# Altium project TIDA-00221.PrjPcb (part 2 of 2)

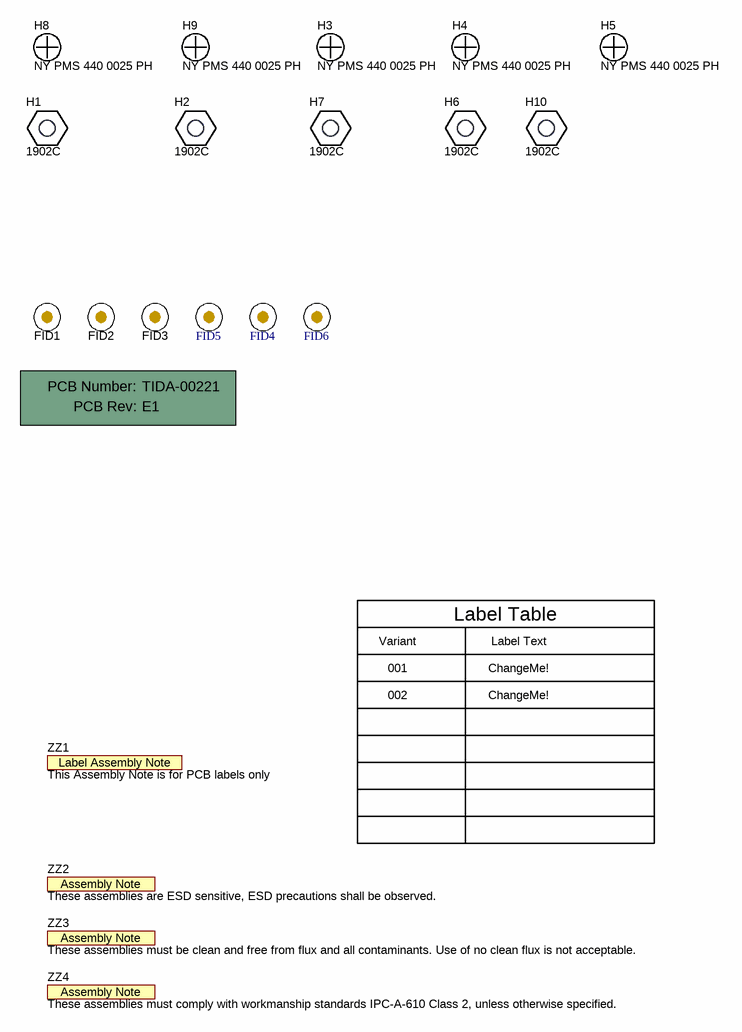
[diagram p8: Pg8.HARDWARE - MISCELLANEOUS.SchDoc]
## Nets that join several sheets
12V: Pg4.Analog Front End Opamp (Voltage) + LDO + ZCD (6 pins), Pg5.JTAG Interface + LEDs + Decoupling Capacitors (R1.2 R2.2)
AGND: Pg3.Analog Front End (Current) (42 pins), Pg4.Analog Front End Opamp (Voltage) + LDO + ZCD (12 pins), Pg5.JTAG Interface + LEDs + Decoupling Capacitors (8 pins), Pg6.MSP430F6779 + Crystal (U3.112 U3.120)
AVCC: Pg4.Analog Front End Opamp (Voltage) + LDO + ZCD (C10.2 R29.1 U2.4), Pg5.JTAG Interface + LEDs + Decoupling Capacitors (C54.1 C55.1 R72.2), Pg6.MSP430F6779 + Crystal (U3.121)
DGND: Pg4.Analog Front End Opamp (Voltage) + LDO + ZCD (11 pins), Pg5.JTAG Interface + LEDs + Decoupling Capacitors (22 pins), Pg6.MSP430F6779 + Crystal (8 pins), Pg7.Interfaces (J1.4)
DVCC: Pg4.Analog Front End Opamp (Voltage) + LDO + ZCD (5 pins), Pg5.JTAG Interface + LEDs + Decoupling Capacitors (9 pins), Pg6.MSP430F6779 + Crystal (5 pins), Pg7.Interfaces (J1.5)
NEUTRAL: Pg3.Analog Front End (Current) (R41.1), Pg4.Analog Front End Opamp (Voltage) + LDO + ZCD (FB1.1 J7.2)
VASYS1: Pg5.JTAG Interface + LEDs + Decoupling Capacitors (C50.1 C51.1 C56.1 C57.1), Pg6.MSP430F6779 + Crystal (U3.111 U3.122)
Active_LED: Pg5.JTAG Interface + LEDs + Decoupling Capacitors (R4.1), Pg6.MSP430F6779 + Crystal (U3.26)
AUXVCC1: Pg5.JTAG Interface + LEDs + Decoupling Capacitors (C41.1 C43.1 TP15.1), Pg6.MSP430F6779 + Crystal (U3.124)
AUXVCC2: Pg5.JTAG Interface + LEDs + Decoupling Capacitors (C40.1 C42.1), Pg6.MSP430F6779 + Crystal (U3.123)
AUXVCC3: Pg5.JTAG Interface + LEDs + Decoupling Capacitors (C47.1 C48.1 TP14.1), Pg6.MSP430F6779 + Crystal (R70.2 U3.3)
Calib_LED: Pg5.JTAG Interface + LEDs + Decoupling Capacitors (R3.1), Pg6.MSP430F6779 + Crystal (U3.27)
I1+: Pg3.Analog Front End (Current) (C18.1 C31.1 R42.1), Pg6.MSP430F6779 + Crystal (U3.103)
I1-: Pg3.Analog Front End (Current) (C18.2 C32.2 R43.1), Pg6.MSP430F6779 + Crystal (U3.104)
I2+: Pg3.Analog Front End (Current) (C19.1 C33.1 R44.1), Pg6.MSP430F6779 + Crystal (U3.105)
I2-: Pg3.Analog Front End (Current) (C19.2 C34.2 R45.1), Pg6.MSP430F6779 + Crystal (U3.106)
I3+: Pg3.Analog Front End (Current) (C20.1 C35.1 R46.1), Pg6.MSP430F6779 + Crystal (U3.107)
I3-: Pg3.Analog Front End (Current) (C20.2 C36.2 R47.1), Pg6.MSP430F6779 + Crystal (U3.108)
I4+: Pg3.Analog Front End (Current) (C21.1 C37.1 R33.1), Pg6.MSP430F6779 + Crystal (U3.109)
I4-: Pg3.Analog Front End (Current) (C21.2 C38.2 R34.1), Pg6.MSP430F6779 + Crystal (U3.110)
I5+: Pg3.Analog Front End (Current) (C22.1 C25.1 R35.1), Pg6.MSP430F6779 + Crystal (U3.114)
I5-: Pg3.Analog Front End (Current) (C22.2 C26.2 R36.1), Pg6.MSP430F6779 + Crystal (U3.115)
I6+: Pg3.Analog Front End (Current) (C23.1 C27.1 R37.1), Pg6.MSP430F6779 + Crystal (U3.116)
I6-: Pg3.Analog Front End (Current) (C23.2 C28.2 R38.1), Pg6.MSP430F6779 + Crystal (U3.117)
I7+: Pg3.Analog Front End (Current) (C24.1 C29.1 R39.1), Pg6.MSP430F6779 + Crystal (U3.118)
I7-: Pg3.Analog Front End (Current) (C24.2 C30.2 R40.1), Pg6.MSP430F6779 + Crystal (U3.119)
P1.0: Pg6.MSP430F6779 + Crystal (U3.11), Pg7.Interfaces (J4.3)
P1.1: Pg6.MSP430F6779 + Crystal (U3.10), Pg7.Interfaces (J4.2)
P1.2: Pg6.MSP430F6779 + Crystal (U3.9), Pg7.Interfaces (J4.1)
P2.4: Pg6.MSP430F6779 + Crystal (U3.12), Pg7.Interfaces (J4.4)
P2.7: Pg6.MSP430F6779 + Crystal (U3.15), Pg7.Interfaces (J1.3)
P3.2: Pg6.MSP430F6779 + Crystal (U3.18), Pg7.Interfaces (J4.7)
P4.3: Pg6.MSP430F6779 + Crystal (U3.41), Pg7.Interfaces (J3.11)
P4.6: Pg6.MSP430F6779 + Crystal (U3.44), Pg7.Interfaces (J3.14)
P4.7: Pg6.MSP430F6779 + Crystal (U3.45), Pg7.Interfaces (J3.15)
P5.5: Pg6.MSP430F6779 + Crystal (R64.1 R65.1 U3.32), Pg7.Interfaces (J3.2)
P5.6: Pg6.MSP430F6779 + Crystal (U3.33), Pg7.Interfaces (J3.3)
P5.7: Pg6.MSP430F6779 + Crystal (U3.34), Pg7.Interfaces (J3.4)
P6.0: Pg6.MSP430F6779 + Crystal (U3.35), Pg7.Interfaces (J3.5)
P6.1: Pg6.MSP430F6779 + Crystal (U3.46), Pg7.Interfaces (J2.1)
P6.2: Pg6.MSP430F6779 + Crystal (U3.47), Pg7.Interfaces (J2.2)
P6.3: Pg6.MSP430F6779 + Crystal (U3.48), Pg7.Interfaces (J2.3)
P6.4: Pg6.MSP430F6779 + Crystal (U3.49), Pg7.Interfaces (J2.4)
P6.5: Pg6.MSP430F6779 + Crystal (U3.50), Pg7.Interfaces (J2.5)
P6.6: Pg6.MSP430F6779 + Crystal (U3.51), Pg7.Interfaces (J2.6)
P6.7: Pg6.MSP430F6779 + Crystal (U3.52), Pg7.Interfaces (J2.7)
P7.0: Pg6.MSP430F6779 + Crystal (U3.53), Pg7.Interfaces (J2.8)
P7.1: Pg6.MSP430F6779 + Crystal (U3.54), Pg7.Interfaces (J2.9)
P7.2: Pg6.MSP430F6779 + Crystal (U3.55), Pg7.Interfaces (J2.10)
P7.3: Pg6.MSP430F6779 + Crystal (U3.56), Pg7.Interfaces (J2.11)
P7.4: Pg6.MSP430F6779 + Crystal (U3.57), Pg7.Interfaces (J2.12)
P7.5: Pg6.MSP430F6779 + Crystal (U3.58), Pg7.Interfaces (J2.13)
P7.6: Pg6.MSP430F6779 + Crystal (U3.59), Pg7.Interfaces (J2.14)
P7.7: Pg6.MSP430F6779 + Crystal (U3.60), Pg7.Interfaces (J2.15)
P8.0: Pg6.MSP430F6779 + Crystal (U3.61), Pg7.Interfaces (J2.16)
P8.1: Pg6.MSP430F6779 + Crystal (U3.62), Pg7.Interfaces (J2.17)
P8.2: Pg6.MSP430F6779 + Crystal (U3.63), Pg7.Interfaces (J2.18)
P8.3: Pg6.MSP430F6779 + Crystal (U3.64), Pg7.Interfaces (J2.19)
P8.4: Pg6.MSP430F6779 + Crystal (U3.65), Pg7.Interfaces (J2.20)
P8.5: Pg6.MSP430F6779 + Crystal (U3.66), Pg7.Interfaces (J2.21)
P8.6: Pg6.MSP430F6779 + Crystal (U3.67), Pg7.Interfaces (J2.22)
P8.7: Pg6.MSP430F6779 + Crystal (U3.68), Pg7.Interfaces (J2.23)
PM_UCA0RXD: Pg6.MSP430F6779 + Crystal (U3.16), Pg7.Interfaces (J1.2)
PM_UCA0TXD: Pg6.MSP430F6779 + Crystal (U3.17), Pg7.Interfaces (J1.1)
PM_UCA1CLK: Pg6.MSP430F6779 + Crystal (U3.19), Pg7.Interfaces (J4.8)
PM_UCA1SIMO: Pg6.MSP430F6779 + Crystal (U3.21), Pg7.Interfaces (J4.10)
PM_UCA1SOMI: Pg6.MSP430F6779 + Crystal (U3.20), Pg7.Interfaces (J4.9)
PM_UCA2CLK: Pg6.MSP430F6779 + Crystal (U3.38), Pg7.Interfaces (J3.8)
PM_UCA2SIMO: Pg6.MSP430F6779 + Crystal (U3.37), Pg7.Interfaces (J3.7)
PM_UCA2SOMI: Pg6.MSP430F6779 + Crystal (U3.36), Pg7.Interfaces (J3.6)
PM_UCA3RXD: Pg6.MSP430F6779 + Crystal (U3.39), Pg7.Interfaces (J3.9)
PM_UCA3TXD: Pg6.MSP430F6779 + Crystal (U3.40), Pg7.Interfaces (J3.10)
PM_UCB0SCL: Pg6.MSP430F6779 + Crystal (R69.1 U3.13), Pg7.Interfaces (J4.5)
PM_UCB0SDA: Pg6.MSP430F6779 + Crystal (R68.1 U3.14), Pg7.Interfaces (J4.6)
PM_UCB1SCL: Pg6.MSP430F6779 + Crystal (R63.1 U3.42), Pg7.Interfaces (J3.12)
PM_UCB1SDA: Pg6.MSP430F6779 + Crystal (R62.1 U3.43), Pg7.Interfaces (J3.13)
RESET: Pg5.JTAG Interface + LEDs + Decoupling Capacitors (5 pins), Pg6.MSP430F6779 + Crystal (U3.102)
SDCLK: Pg6.MSP430F6779 + Crystal (R65.2 R67.1 U3.31), Pg7.Interfaces (J3.1)
TCK: Pg5.JTAG Interface + LEDs + Decoupling Capacitors (J8.7 R17.2), Pg6.MSP430F6779 + Crystal (U3.101)
TDI: Pg5.JTAG Interface + LEDs + Decoupling Capacitors (J8.3 R8.2), Pg6.MSP430F6779 + Crystal (U3.99)
TDO: Pg5.JTAG Interface + LEDs + Decoupling Capacitors (J8.1 R5.2), Pg6.MSP430F6779 + Crystal (U3.98)
TEST/SBWTCK: Pg5.JTAG Interface + LEDs + Decoupling Capacitors (J8.8), Pg6.MSP430F6779 + Crystal (U3.97)
TMS: Pg5.JTAG Interface + LEDs + Decoupling Capacitors (J8.5 R13.2), Pg6.MSP430F6779 + Crystal (U3.100)
V1_IN_H: Pg4.Analog Front End Opamp (Voltage) + LDO + ZCD (C6.2 R6.2), Pg6.MSP430F6779 + Crystal (U3.6)
V1_IN_L: Pg4.Analog Front End Opamp (Voltage) + LDO + ZCD (C5.2 R7.2 R24.2), Pg6.MSP430F6779 + Crystal (U3.7)
V_ZCD: Pg4.Analog Front End Opamp (Voltage) + LDO + ZCD (C16.1 R32.2 U2.8), Pg6.MSP430F6779 + Crystal (U3.8)
VCORE: Pg5.JTAG Interface + LEDs + Decoupling Capacitors (C46.1), Pg6.MSP430F6779 + Crystal (U3.128)
VDSYS1: Pg5.JTAG Interface + LEDs + Decoupling Capacitors (C39.1 C49.1), Pg6.MSP430F6779 + Crystal (C53.2 R70.1 U3.69 U3.125)
VREF: Pg5.JTAG Interface + LEDs + Decoupling Capacitors (C52.1), Pg6.MSP430F6779 + Crystal (U3.113)

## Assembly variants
001: not fitted C5 C6 C8 C9 C10 C12 C16 C40 C43 FB1 FB3 J7 R6 R7 R9 R10 R11 R12 R14 R15 R18 R19 R20 R22 R23 R24 R25 R26 R27 R28 R29 R30 R31 R32 R41 R48 R49 R50 R51 R52 R53 R55 R64 R65 R67 R91 R92 TP3 TP6 TP13 U2 U4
